VERSION 5.7 ;
  NOWIREEXTENSIONATPIN ON ;
  DIVIDERCHAR "/" ;
  BUSBITCHARS "[]" ;
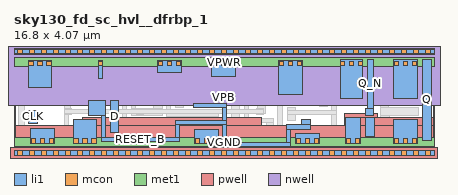
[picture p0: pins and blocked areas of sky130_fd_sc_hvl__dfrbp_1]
MACRO sky130_fd_sc_hvl__dfrbp_1
  CLASS BLOCK ;
  FOREIGN sky130_fd_sc_hvl__dfrbp_1 ;
  ORIGIN 0.000 0.000 ;
  SIZE 16.800 BY 4.070 ;
  PIN CLK
    ANTENNAGATEAREA 0.585000 ;
    PORT
      LAYER li1 ;
        RECT 0.595 1.175 0.925 1.720 ;
    END
  END CLK
  PIN D
    ANTENNAGATEAREA 0.420000 ;
    PORT
      LAYER li1 ;
        RECT 3.850 0.810 4.165 2.105 ;
    END
  END D
  PIN RESET_B
    ANTENNAGATEAREA 1.260000 ;
    PORT
      LAYER li1 ;
        RECT 2.980 1.505 3.665 2.120 ;
        RECT 7.165 1.825 8.515 1.995 ;
        RECT 3.495 0.630 3.665 1.505 ;
        RECT 8.345 1.295 8.515 1.825 ;
        RECT 6.455 1.125 8.515 1.295 ;
        RECT 11.510 1.130 11.840 1.350 ;
        RECT 6.455 0.630 6.625 1.125 ;
        RECT 3.495 0.460 6.625 0.630 ;
        RECT 8.345 0.435 8.515 1.125 ;
        RECT 10.905 0.960 11.840 1.130 ;
        RECT 10.905 0.435 11.075 0.960 ;
        RECT 8.345 0.265 11.075 0.435 ;
    END
  END RESET_B
  PIN VGND
    USE GROUND ;
    PORT
      LAYER li1 ;
        RECT 0.675 0.365 1.625 0.995 ;
        RECT 2.365 0.365 3.315 1.325 ;
        RECT 7.215 0.365 8.165 0.945 ;
        RECT 11.255 0.365 12.205 0.780 ;
        RECT 13.255 0.365 13.845 1.495 ;
        RECT 15.195 0.365 16.145 1.325 ;
      LAYER mcon ;
        RECT 0.705 0.395 0.875 0.565 ;
        RECT 1.065 0.395 1.235 0.565 ;
        RECT 1.425 0.395 1.595 0.565 ;
        RECT 2.395 0.395 2.565 0.565 ;
        RECT 2.755 0.395 2.925 0.565 ;
        RECT 3.115 0.395 3.285 0.565 ;
        RECT 7.245 0.395 7.415 0.565 ;
        RECT 7.605 0.395 7.775 0.565 ;
        RECT 7.965 0.395 8.135 0.565 ;
        RECT 11.285 0.395 11.455 0.565 ;
        RECT 11.645 0.395 11.815 0.565 ;
        RECT 12.005 0.395 12.175 0.565 ;
        RECT 13.285 0.395 13.455 0.565 ;
        RECT 13.645 0.395 13.815 0.565 ;
        RECT 15.225 0.395 15.395 0.565 ;
        RECT 15.585 0.395 15.755 0.565 ;
        RECT 15.945 0.395 16.115 0.565 ;
      LAYER met1 ;
        RECT 0.000 0.255 16.800 0.625 ;
    END
  END VGND
  PIN VNB
    ANTENNADIFFAREA 2.856000 ;
    PORT
      LAYER pwell ;
        RECT 13.205 1.415 14.535 1.585 ;
        RECT 2.725 1.085 9.880 1.415 ;
        RECT 13.205 1.085 16.780 1.415 ;
        RECT 0.055 0.215 16.780 1.085 ;
        RECT -0.130 -0.215 16.930 0.215 ;
      LAYER li1 ;
        RECT 0.000 -0.085 16.800 0.085 ;
      LAYER mcon ;
        RECT 0.155 -0.085 0.325 0.085 ;
        RECT 0.635 -0.085 0.805 0.085 ;
        RECT 1.115 -0.085 1.285 0.085 ;
        RECT 1.595 -0.085 1.765 0.085 ;
        RECT 2.075 -0.085 2.245 0.085 ;
        RECT 2.555 -0.085 2.725 0.085 ;
        RECT 3.035 -0.085 3.205 0.085 ;
        RECT 3.515 -0.085 3.685 0.085 ;
        RECT 3.995 -0.085 4.165 0.085 ;
        RECT 4.475 -0.085 4.645 0.085 ;
        RECT 4.955 -0.085 5.125 0.085 ;
        RECT 5.435 -0.085 5.605 0.085 ;
        RECT 5.915 -0.085 6.085 0.085 ;
        RECT 6.395 -0.085 6.565 0.085 ;
        RECT 6.875 -0.085 7.045 0.085 ;
        RECT 7.355 -0.085 7.525 0.085 ;
        RECT 7.835 -0.085 8.005 0.085 ;
        RECT 8.315 -0.085 8.485 0.085 ;
        RECT 8.795 -0.085 8.965 0.085 ;
        RECT 9.275 -0.085 9.445 0.085 ;
        RECT 9.755 -0.085 9.925 0.085 ;
        RECT 10.235 -0.085 10.405 0.085 ;
        RECT 10.715 -0.085 10.885 0.085 ;
        RECT 11.195 -0.085 11.365 0.085 ;
        RECT 11.675 -0.085 11.845 0.085 ;
        RECT 12.155 -0.085 12.325 0.085 ;
        RECT 12.635 -0.085 12.805 0.085 ;
        RECT 13.115 -0.085 13.285 0.085 ;
        RECT 13.595 -0.085 13.765 0.085 ;
        RECT 14.075 -0.085 14.245 0.085 ;
        RECT 14.555 -0.085 14.725 0.085 ;
        RECT 15.035 -0.085 15.205 0.085 ;
        RECT 15.515 -0.085 15.685 0.085 ;
        RECT 15.995 -0.085 16.165 0.085 ;
        RECT 16.475 -0.085 16.645 0.085 ;
      LAYER met1 ;
        RECT 0.000 -0.115 16.800 0.115 ;
    END
  END VNB
  PIN VPB
    ANTENNADIFFAREA 2.856000 ;
    PORT
      LAYER nwell ;
        RECT -0.330 1.885 17.130 4.485 ;
      LAYER li1 ;
        RECT 0.000 3.985 16.800 4.155 ;
      LAYER mcon ;
        RECT 0.155 3.985 0.325 4.155 ;
        RECT 0.635 3.985 0.805 4.155 ;
        RECT 1.115 3.985 1.285 4.155 ;
        RECT 1.595 3.985 1.765 4.155 ;
        RECT 2.075 3.985 2.245 4.155 ;
        RECT 2.555 3.985 2.725 4.155 ;
        RECT 3.035 3.985 3.205 4.155 ;
        RECT 3.515 3.985 3.685 4.155 ;
        RECT 3.995 3.985 4.165 4.155 ;
        RECT 4.475 3.985 4.645 4.155 ;
        RECT 4.955 3.985 5.125 4.155 ;
        RECT 5.435 3.985 5.605 4.155 ;
        RECT 5.915 3.985 6.085 4.155 ;
        RECT 6.395 3.985 6.565 4.155 ;
        RECT 6.875 3.985 7.045 4.155 ;
        RECT 7.355 3.985 7.525 4.155 ;
        RECT 7.835 3.985 8.005 4.155 ;
        RECT 8.315 3.985 8.485 4.155 ;
        RECT 8.795 3.985 8.965 4.155 ;
        RECT 9.275 3.985 9.445 4.155 ;
        RECT 9.755 3.985 9.925 4.155 ;
        RECT 10.235 3.985 10.405 4.155 ;
        RECT 10.715 3.985 10.885 4.155 ;
        RECT 11.195 3.985 11.365 4.155 ;
        RECT 11.675 3.985 11.845 4.155 ;
        RECT 12.155 3.985 12.325 4.155 ;
        RECT 12.635 3.985 12.805 4.155 ;
        RECT 13.115 3.985 13.285 4.155 ;
        RECT 13.595 3.985 13.765 4.155 ;
        RECT 14.075 3.985 14.245 4.155 ;
        RECT 14.555 3.985 14.725 4.155 ;
        RECT 15.035 3.985 15.205 4.155 ;
        RECT 15.515 3.985 15.685 4.155 ;
        RECT 15.995 3.985 16.165 4.155 ;
        RECT 16.475 3.985 16.645 4.155 ;
      LAYER met1 ;
        RECT 0.000 3.955 16.800 4.185 ;
    END
  END VPB
  PIN VPWR
    USE POWER ;
    PORT
      LAYER li1 ;
        RECT 0.595 2.625 1.485 3.705 ;
        RECT 3.385 3.000 3.555 3.705 ;
        RECT 5.745 3.225 6.685 3.705 ;
        RECT 7.915 3.050 8.865 3.705 ;
        RECT 10.590 2.350 11.540 3.705 ;
        RECT 13.060 2.175 13.950 3.755 ;
        RECT 15.175 2.175 16.125 3.755 ;
      LAYER mcon ;
        RECT 0.595 3.505 0.765 3.675 ;
        RECT 0.955 3.505 1.125 3.675 ;
        RECT 1.315 3.505 1.485 3.675 ;
        RECT 3.385 3.505 3.555 3.675 ;
        RECT 5.770 3.505 5.940 3.675 ;
        RECT 6.130 3.505 6.300 3.675 ;
        RECT 6.490 3.505 6.660 3.675 ;
        RECT 7.945 3.505 8.115 3.675 ;
        RECT 8.305 3.505 8.475 3.675 ;
        RECT 8.665 3.505 8.835 3.675 ;
        RECT 10.620 3.505 10.790 3.675 ;
        RECT 10.980 3.505 11.150 3.675 ;
        RECT 11.340 3.505 11.510 3.675 ;
        RECT 13.060 3.505 13.230 3.675 ;
        RECT 13.420 3.505 13.590 3.675 ;
        RECT 13.780 3.505 13.950 3.675 ;
        RECT 15.205 3.505 15.375 3.675 ;
        RECT 15.565 3.505 15.735 3.675 ;
        RECT 15.925 3.505 16.095 3.675 ;
      LAYER met1 ;
        RECT 0.000 3.445 16.800 3.815 ;
    END
  END VPWR
  PIN Q
    ANTENNADIFFAREA 0.626250 ;
    PORT
      LAYER li1 ;
        RECT 16.340 0.515 16.690 3.755 ;
    END
  END Q
  PIN Q_N
    ANTENNADIFFAREA 0.641250 ;
    PORT
      LAYER li1 ;
        RECT 14.130 1.780 14.380 3.755 ;
        RECT 14.045 1.495 14.380 1.780 ;
        RECT 14.045 0.665 14.425 1.495 ;
    END
  END Q_N
  OBS
      LAYER li1 ;
        RECT 1.665 3.635 3.205 3.805 ;
        RECT 0.165 2.445 0.415 3.455 ;
        RECT 1.665 2.445 1.835 3.635 ;
        RECT 0.165 2.275 1.835 2.445 ;
        RECT 0.165 0.995 0.415 2.275 ;
        RECT 1.505 1.900 1.835 2.275 ;
        RECT 2.015 1.550 2.275 3.455 ;
        RECT 2.525 2.470 2.855 3.420 ;
        RECT 3.035 2.820 3.205 3.635 ;
        RECT 3.735 3.600 5.565 3.770 ;
        RECT 3.735 2.820 3.905 3.600 ;
        RECT 4.085 3.000 4.515 3.420 ;
        RECT 4.865 3.000 5.215 3.420 ;
        RECT 3.035 2.650 3.905 2.820 ;
        RECT 4.345 2.470 4.515 3.000 ;
        RECT 2.525 2.300 4.515 2.470 ;
        RECT 2.015 0.995 2.185 1.550 ;
        RECT 0.165 0.495 0.495 0.995 ;
        RECT 1.805 0.495 2.185 0.995 ;
        RECT 4.345 1.325 4.515 2.300 ;
        RECT 4.695 1.780 4.865 2.820 ;
        RECT 5.045 2.370 5.215 3.000 ;
        RECT 5.395 3.045 5.565 3.600 ;
        RECT 6.865 3.635 7.735 3.805 ;
        RECT 6.865 3.045 7.035 3.635 ;
        RECT 5.395 2.875 7.035 3.045 ;
        RECT 5.395 2.550 5.650 2.875 ;
        RECT 7.215 2.695 7.385 3.455 ;
        RECT 7.565 2.870 7.735 3.635 ;
        RECT 7.565 2.700 9.375 2.870 ;
        RECT 6.105 2.525 7.385 2.695 ;
        RECT 6.105 2.370 6.275 2.525 ;
        RECT 5.045 2.200 6.275 2.370 ;
        RECT 8.695 2.345 9.025 2.520 ;
        RECT 5.595 1.780 5.925 2.020 ;
        RECT 4.695 1.505 5.925 1.780 ;
        RECT 6.105 1.645 6.275 2.200 ;
        RECT 6.455 2.175 9.025 2.345 ;
        RECT 6.455 1.825 6.785 2.175 ;
        RECT 6.105 1.475 8.165 1.645 ;
        RECT 6.105 1.325 6.275 1.475 ;
        RECT 4.345 0.825 4.655 1.325 ;
        RECT 5.270 1.155 6.275 1.325 ;
        RECT 5.270 0.825 5.600 1.155 ;
        RECT 8.695 0.615 9.025 2.175 ;
        RECT 9.205 1.400 9.375 2.700 ;
        RECT 9.555 2.440 9.805 3.350 ;
        RECT 11.965 2.520 12.295 2.770 ;
        RECT 9.555 2.270 10.410 2.440 ;
        RECT 11.965 2.350 12.880 2.520 ;
        RECT 10.240 2.170 10.410 2.270 ;
        RECT 9.725 1.580 10.060 2.090 ;
        RECT 10.240 2.000 12.530 2.170 ;
        RECT 9.205 1.230 10.375 1.400 ;
        RECT 10.090 1.070 10.375 1.230 ;
        RECT 9.580 0.785 9.910 0.995 ;
        RECT 10.555 0.785 10.725 2.000 ;
        RECT 12.200 1.880 12.530 2.000 ;
        RECT 10.930 1.700 11.260 1.820 ;
        RECT 12.710 1.700 12.880 2.350 ;
        RECT 10.930 1.530 12.880 1.700 ;
        RECT 10.930 1.310 11.260 1.530 ;
        RECT 9.580 0.615 10.725 0.785 ;
        RECT 12.710 0.975 12.880 1.530 ;
        RECT 14.665 1.835 14.995 3.005 ;
        RECT 14.665 1.505 16.160 1.835 ;
        RECT 12.710 0.515 13.075 0.975 ;
        RECT 14.665 0.825 15.015 1.505 ;
      LAYER mcon ;
        RECT 2.075 1.580 2.245 1.750 ;
        RECT 4.955 1.580 5.125 1.750 ;
        RECT 9.755 1.580 9.925 1.750 ;
      LAYER met1 ;
        RECT 2.015 1.735 2.305 1.780 ;
        RECT 4.895 1.735 5.185 1.780 ;
        RECT 9.695 1.735 9.985 1.780 ;
        RECT 2.015 1.595 9.985 1.735 ;
        RECT 2.015 1.550 2.305 1.595 ;
        RECT 4.895 1.550 5.185 1.595 ;
        RECT 9.695 1.550 9.985 1.595 ;
  END
END sky130_fd_sc_hvl__dfrbp_1
END LIBRARY

